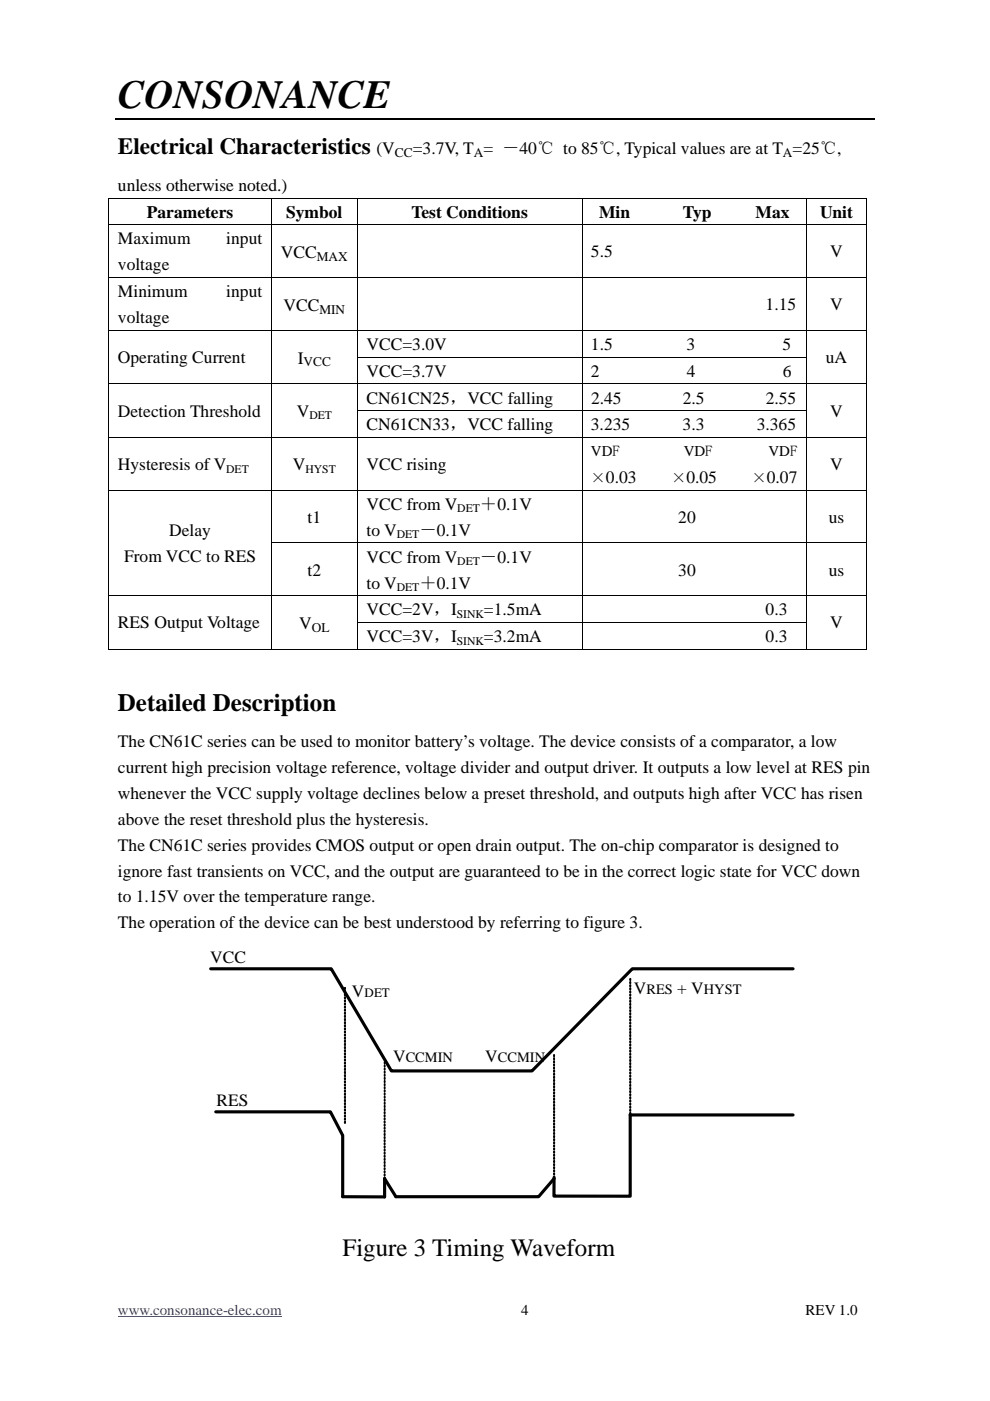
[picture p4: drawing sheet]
<svg xmlns="http://www.w3.org/2000/svg" width="210mm" height="297mm" viewBox="0 0 210 297" stroke-linecap="round" stroke-linejoin="round" font-family="sans-serif">
<defs><g id="words">
<text font-size="8.5" x="25" y="22.9">CONSONANCE</text>
<g font-size="5.3">
<text x="25" y="150.7">Detailed Description</text>
<text x="72.6" y="266.2">Figure 3 Timing Waveform</text>
</g>
<text font-size="4.9" x="25" y="32.7">Electrical Characteristics</text>
<g font-size="3.7">
<text x="79.9" y="32.7">(V</text>
<text x="87.5" y="32.7">=3.7V, T = －40℃ to 85℃, Typical values are at T =25℃,</text>
<text x="25" y="40.5">unless otherwise noted.)</text>
<text x="31.2" y="46.2">Parameters</text>
<text x="60.7" y="46.2">Symbol</text>
<text x="87.3" y="46.2">Test Conditions</text>
<text x="127.1" y="46.2">Min</text>
<text x="144.8" y="46.2">Typ</text>
<text x="160.3" y="46.2">Max</text>
<text x="173.9" y="46.2">Unit</text>
<text x="25" y="51.8">Maximum</text>
<text x="48" y="51.8">input</text>
<text x="25" y="57.3">voltage</text>
<text x="59.6" y="54.8">VCC</text>
<text x="125.3" y="54.6">5.5</text>
<text x="176.1" y="54.6">V</text>
<text x="25" y="63">Minimum</text>
<text x="48" y="63">input</text>
<text x="60.1" y="66">VCC</text>
<text x="162.4" y="65.8">1.15</text>
<text x="176.1" y="65.8">V</text>
<text x="25" y="68.5">voltage</text>
<text x="25" y="76.9">Operating Current</text>
<text x="63.2" y="77.1">I</text>
<text x="77.7" y="74.2">VCC=3.0V</text>
<text x="125.4" y="74.2">1.5</text>
<text x="145.6" y="74.2">3</text>
<text x="165.9" y="74.2">5</text>
<text x="175.2" y="76.9">uA</text>
<text x="77.7" y="79.9">VCC=3.7V</text>
<text x="125.3" y="79.9">2</text>
<text x="145.7" y="79.9">4</text>
<text x="166.1" y="79.9">6</text>
<text x="25" y="88.3">Detection Threshold</text>
<text x="63" y="88.3">V</text>
<text x="77.7" y="85.6">CN61CN25，VCC falling</text>
<text x="125.4" y="85.6">2.45</text>
<text x="144.8" y="85.6">2.5</text>
<text x="162.4" y="85.6">2.55</text>
<text x="176.1" y="88.3">V</text>
<text x="77.7" y="91.2">CN61CN33，VCC falling</text>
<text x="125.3" y="91.2">3.235</text>
<text x="144.8" y="91.2">3.3</text>
<text x="160.5" y="91.2">3.365</text>
<text x="25" y="99.7">Hysteresis of V</text>
<text x="62.1" y="99.7">V</text>
<text x="77.7" y="99.7">VCC rising</text>
<text x="176.1" y="99.7">V</text>
<text x="128.5" y="102.3">0.03</text>
<text x="145.6" y="102.3">0.05</text>
<text x="162.7" y="102.3">0.07</text>
<text x="35.9" y="113.6">Delay</text>
<text x="65.2" y="110.8">t1</text>
<text x="77.7" y="108.1">VCC from V</text>
<text x="77.7" y="113.6">to V</text>
<text x="88.9" y="113.6">－0.1V</text>
<text x="101.8" y="108.1">＋0.1V</text>
<text x="143.9" y="110.8">20</text>
<text x="175.8" y="110.8">us</text>
<text x="26.3" y="119.1">From VCC to RES</text>
<text x="77.7" y="119.3">VCC from V</text>
<text x="101.8" y="119.3">－0.1V</text>
<text x="65.2" y="122">t2</text>
<text x="77.7" y="124.8">to V</text>
<text x="88.9" y="124.8">＋0.1V</text>
<text x="143.9" y="122">30</text>
<text x="175.8" y="122">us</text>
<text x="77.7" y="130.5">VCC=2V，I</text>
<text x="102.6" y="130.5">=1.5mA</text>
<text x="162.4" y="130.5">0.3</text>
<text x="25" y="133.2">RES Output Voltage</text>
<text x="63.5" y="133.4">V</text>
<text x="77.7" y="136.1">VCC=3V，I</text>
<text x="102.6" y="136.1">=3.2mA</text>
<text x="162.4" y="136.1">0.3</text>
<text x="176.1" y="133.2">V</text>
<text x="25" y="158.3">The CN61C series can be used to monitor battery’s voltage. The device consists of a comparator, a low</text>
<text x="25" y="163.8">current high precision voltage reference, voltage divider and output driver. It outputs a low level at RES pin</text>
<text x="25" y="169.3">whenever the VCC supply voltage declines below a preset threshold, and outputs high after VCC has risen</text>
<text x="25" y="174.8">above the reset threshold plus the hysteresis.</text>
<text x="25" y="180.3">The CN61C series provides CMOS output or open drain output. The on-chip comparator is designed to</text>
<text x="25" y="185.8">ignore fast transients on VCC, and the output are guaranteed to be in the correct logic state for VCC down</text>
<text x="25" y="191.3">to 1.15V over the temperature range.</text>
<text x="25" y="196.8">The operation of the device can be best understood by referring to figure 3.</text>
<text x="44.6" y="204.2">VCC</text>
<text x="74.7" y="211.5">V</text>
<text x="134.5" y="210.8">V</text>
<text x="143.6" y="210.8">+ V</text>
<text x="83.4" y="225.1">V</text>
<text x="102.9" y="225.1">V</text>
<text x="46" y="234.5">RES</text>
</g>
<g font-size="3.2">
<text x="125.3" y="96.7">VDF</text>
<text x="145" y="96.7">VDF</text>
<text x="163" y="96.7">VDF</text>
<text x="125.3" y="102.3">×</text>
<text x="142.4" y="102.3">×</text>
<text x="159.5" y="102.3">×</text>
<text x="110.5" y="278.7">4</text>
<text x="170.9" y="278.7">REV 1.0</text>
</g>
<text font-size="3.2" fill="#00f" x="25" y="278.7">www.consonance-elec.com</text>
<g font-size="3">
<text x="137.1" y="210.8">RES</text>
<text x="149.3" y="210.8">HYST</text>
<text x="86" y="225.1">CCMIN</text>
<text x="105.6" y="225.1">CCMIN</text>
</g>
<g font-size="2.8">
<text x="83.8" y="33.3">CC</text>
<text x="100.5" y="33.3">A</text>
<text x="166.1" y="33.3">A</text>
<text x="67.2" y="55.3">MAX</text>
<text x="67.8" y="66.5">MIN</text>
<text x="64.4" y="77.7">VCC</text>
<text x="66.1" y="133.9">OL</text>
<text x="77.3" y="211.5">DET</text>
</g>
<g font-size="2.5">
<text x="65.6" y="88.8">DET</text>
<text x="48" y="100.2">DET</text>
<text x="64.8" y="100.2">HYST</text>
<text x="97" y="108.6">DET</text>
<text x="84.2" y="114.1">DET</text>
<text x="97" y="119.8">DET</text>
<text x="84.2" y="125.3">DET</text>
<text x="96.9" y="131">SINK</text>
<text x="96.9" y="136.7">SINK</text>
</g>
</g></defs>
<path d="M24.5 25.2h161" fill="none" stroke="#000" stroke-width=".25"/>
<path d="M25 279.2h34.7" fill="none" stroke="#00f" stroke-width=".21"/>
<g fill="#000">
<path d="M23 41.9h.2v.2h-.2zM183.7 41.9h.2v.2h-.2zM23 75.6h.2v.2h-.2zM57.4 75.6h.2v.2h-.2zM183.7 75.6h.2v.2h-.2zM23 87h.2v.2h-.2zM57.4 87h.2v.2h-.2zM183.7 87h.2v.2h-.2zM23 115h.2v.2h-.2zM23 131.9h.2v.2h-.2zM57.4 131.9h.2v.2h-.2zM183.7 131.9h.2v.2h-.2z"/>
<path d="M183.7 137.6h.2v.2h-.2z"/>
</g>
<g fill="none" stroke="#000" stroke-width=".21">
<path d="M23 42h160.9M23 47.7h160.9M23 58.9h160.9M23.1 42.1v5.5M23.1 47.8v11M23.1 58.9v11.1M57.5 42.1v5.5M57.5 47.8v11M57.5 58.9v11.1M75.8 42.1v5.5M75.8 47.8v11M75.8 58.9v11.1"/>
<path d="M123.4 42.1v5.5M123.4 47.8v11M123.4 58.9v11.1M171.1 42.1v5.5M171.1 47.8v11M171.1 58.9v11.1M183.8 42.1v5.5M183.8 47.8v11M183.8 58.9v11.1M23 70h160.9M23.1 70.1v5.5M23.1 75.8v5.5"/>
<path d="M57.5 70.1v5.5M57.5 75.8v5.5M75.7 75.7h95.5M75.8 70.1v5.5M75.8 75.8v5.5M123.4 70.1v5.5M123.4 75.8v5.5M171.1 70.1v5.5M171.1 75.8v5.5M183.8 70.1v5.5M183.8 75.8v5.5M23 81.4h160.9"/>
<path d="M23 92.8h160.9M23.1 81.5v5.5M23.1 87.2v5.5M23.1 92.8v11.1M57.5 81.5v5.5M57.5 87.2v5.5M57.5 92.8v11.1M75.7 87.1h95.5M75.8 81.5v5.5M75.8 87.2v5.5M75.8 92.8v11.1M123.4 81.5v5.5"/>
<path d="M123.4 87.2v5.5M123.4 92.8v11.1M171.1 81.5v5.5M171.1 87.2v5.5M171.1 92.8v11.1M183.8 81.5v5.5M183.8 87.2v5.5M183.8 92.8v11.1M23 103.9h160.9M23.1 104v11M23.1 115.2v11M57.4 115.1h126.5"/>
<path d="M57.5 104v11M57.5 115.2v11M75.8 104v11M75.8 115.2v11M123.4 104v11M123.4 115.2v11M171.1 104v11M171.1 115.2v11M183.8 104v11M183.8 115.2v11M23 126.3h160.9M23 137.7h34.4"/>
<path d="M23.1 126.4v5.5M23.1 132.1v5.7M57.5 126.4v5.5M57.5 132.1v5.7M57.6 137.7h18.1M75.7 132h95.5M75.8 126.4v5.5M75.8 132.1v5.7M75.9 137.7h47.5M123.4 126.4v5.5M123.4 132.1v5.7M123.5 137.7h47.5"/>
<path d="M171.1 126.4v5.5M171.1 132.1v5.7M171.2 137.7h12.5M183.8 126.4v5.5M183.8 132.1v5.7"/>
</g>
<path d="M44.7 205.4h25.6l12.7 21.7h29.8l21.3-21.7h34.1M45.8 235.7h24.3l2.6 5v13l8.9 .1v-3.9l2.4 3.8h30.2l3.3-3.8M133.7 236.3v17.3h-16.2v-4M133.7 236.4h34.5" fill="none" stroke="#000" stroke-width=".66"/>
<g fill="#000" stroke="#000" stroke-width=".21">
<path d="M73 209.4h.3v.3h-.3zM73.1 210h.2v.4l-.3-.1zM73.1 210.7h.2v.4l-.3-.1zM73.1 211.3h.2v.4l-.3-.1zM73.1 212l.2 .1-.1 .3-.2-.1zM73 212.7h.3v.3h-.3zM73.1 213.3h.2v.4l-.3-.1zM73.1 214h.2v.4l-.3-.1zM73.1 214.7h.2v.3l-.3-.1zM73.1 215.3l.2 .1-.1 .3-.2-.1zM73 216h.3v.3h-.3zM73.1 216.6h.2v.4l-.3-.1zM73.1 217.3h.2v.4l-.3-.1zM73.1 218h.2v.3l-.3-.1zM73.1 218.6l.2 .1-.1 .3-.2-.1zM73.1 219.3l.2 .1-.1 .3-.2-.1zM73.1 219.9h.2v.4l-.3-.1zM73.1 220.6h.2v.4l-.3-.1zM73.1 221.3h.2v.3h-.3zM73.1 221.9l.2 .1-.1 .3-.2-.1zM73.1 222.6l.2 .1-.1 .3-.2-.1zM73.1 223.2h.2v.4l-.3-.1zM73.1 223.9h.2v.4l-.3-.1zM73.1 224.6h.2v.3h-.3zM73.1 225.2l.2 .1-.1 .3-.2-.1zM73.1 225.9l.2 .1-.1 .3-.2-.1zM73.1 226.5h.2v.4l-.3-.1zM73.1 227.2h.2v.4l-.3-.1zM73.1 227.9h.2v.3h-.3zM73.1 228.5l.2 .1-.1 .3-.2-.1zM73.1 229.2l.2 .1-.1 .3-.2-.1zM73.1 229.8h.2v.4l-.3-.1zM73.1 230.5h.2v.4l-.3-.1zM73.1 231.2h.2v.3h-.3zM73.1 231.8l.2 .1-.1 .3-.2-.1zM73.1 232.5l.2 .1-.1 .3-.2-.1zM73.1 233.2h.2v.3l-.3-.1zM73.1 233.8h.2v.4l-.3-.1zM73.1 234.5h.2v.3h-.3zM73.1 235.1l.2 .1-.1 .3-.2-.1zM73.1 235.8l.2 .1-.1 .3-.2-.1zM73.1 236.5h.2v.3l-.3-.1zM73.1 237.1h.2v.4l-.3-.1zM73.1 237.8h.2l-.1 .4-.2-.1z"/>
<path d="M133.6 207.5h.2v.4l-.2-.1zM133.6 208.1h.2v.4h-.2zM133.6 208.8h.2v.4l-.2-.1zM133.6 209.5h.2l-.1 .4zM133.7 210.1l.1 .1-.1 .3zM133.6 210.8h.2v.4l-.2-.1zM133.6 211.4h.2v.4h-.2zM133.6 212.1h.2v.4l-.2-.1zM133.6 212.8h.2l-.1 .4zM133.7 213.4l.1 .1-.1 .3zM133.6 214.1h.2v.4l-.2-.1zM133.6 214.7h.2v.4h-.2zM133.6 215.4h.2v.4l-.2-.1zM133.6 216.1h.2l-.1 .4zM133.7 216.7l.1 .1-.1 .3zM133.6 217.4h.2v.4l-.2-.1zM133.6 218h.2v.4h-.2zM133.6 218.7h.2v.4l-.2-.1zM133.6 219.4h.2l-.1 .4zM133.7 220l.1 .1-.1 .3zM133.6 220.7h.2v.4l-.2-.1zM133.6 221.3h.2v.4h-.2zM133.6 222h.2v.4l-.2-.1zM133.6 222.7h.2l-.1 .4zM133.6 223.4h.2v.3l-.2-.1zM133.6 224h.2v.4l-.2-.1zM133.6 224.6h.2v.4h-.2zM133.6 225.3h.2v.4l-.2-.1zM133.6 226h.2l-.1 .4zM133.7 226.6l.1 .1-.1 .3zM133.6 227.3h.2v.4l-.2-.1zM133.6 227.9h.2v.4h-.2zM133.6 228.6h.2v.4l-.2-.1zM133.6 229.3h.2l-.1 .4zM133.7 229.9l.1 .1-.1 .3zM133.6 230.6h.2v.4l-.2-.1zM133.6 231.2h.2v.4h-.2zM133.6 231.9h.2v.4l-.2-.1zM133.6 232.6h.2l-.1 .4zM133.6 233.3h.2v.3h-.2zM133.6 233.9h.2v.4l-.2-.1zM133.6 234.5h.2v.4h-.2zM133.6 235.2h.2v.4l-.2-.1zM133.6 235.9h.2l-.1 .4z"/>
<path d="M117.4 223.6l.2 .1-.1 .3zM117.4 224.3h.2l-.1 .4zM117.4 224.9h.2v.4h-.2zM117.4 225.6h.2v.4h-.2zM117.4 226.3h.2v.4h-.2zM117.4 226.9l.2 .1-.1 .3zM117.4 227.6h.2l-.1 .4zM117.4 228.2l.2 .1v.3h-.2zM117.4 228.9l.2 .1v.3h-.2zM117.4 229.6h.2v.4h-.2zM117.4 230.2l.2 .1-.1 .3zM117.4 230.9h.2l-.1 .4zM117.4 231.5l.2 .1v.3h-.2zM117.4 232.2l.2 .1v.3h-.2zM117.4 232.9h.2v.4h-.2zM117.4 233.5l.2 .1-.1 .3zM117.4 234.2l.2 .1-.1 .3zM117.4 234.8l.2 .1v.3h-.2zM117.4 235.5l.2 .1v.3h-.2zM117.4 236.2h.2v.4h-.2zM117.4 236.8l.2 .1-.1 .3zM117.4 237.5l.2 .1-.1 .3zM117.4 238.1l.2 .1v.3h-.2zM117.4 238.8l.2 .1v.3l-.2-.1zM117.5 239.5l.1 .1v.3l-.2-.1zM117.5 240.1l.1 .1-.1 .3zM117.5 240.8l.1 .1-.1 .3zM117.5 241.4l.1 .1v.3h-.2zM117.5 242.1l.1 .1v.3l-.2-.1zM117.5 242.8l.1 .1v.3l-.2-.1zM117.5 243.4l.1 .1-.1 .3zM117.5 244.1l.1 .1-.1 .3zM117.5 244.8h.1v.3h-.2zM117.5 245.4l.1 .1v.3l-.2-.1zM117.5 246.1l.1 .1v.3l-.2-.1zM117.5 246.7l.1 .1-.1 .3zM117.5 247.4l.1 .1-.1 .3zM117.5 248.1h.1v.3h-.2zM117.5 248.7l.1 .1v.3l-.2-.1zM117.5 249.4l.1 .1-.1 .3z"/>
<path d="M81.5 249.6l.2 .1-.1 .3zM81.6 248.9v.4zM81.5 248.3h.2l-.1 .4zM81.5 247.6l.2 .1-.1 .3zM81.5 246.9l.2 .1-.1 .4zM81.5 246.3h.2v.4l-.2-.1zM81.5 245.6l.2 .1-.1 .3zM81.5 245h.2l-.1 .4zM81.5 244.3h.2v.4l-.2-.1zM81.5 243.6h.2v.4l-.2-.1zM81.5 243h.2v.4l-.2-.1zM81.6 242.3v.4zM81.5 241.7h.2l-.1 .4zM81.5 241h.2v.4l-.2-.1zM81.5 240.3h.2v.4l-.2-.1zM81.5 239.7h.2v.4l-.2-.1zM81.5 239l.2 .1-.1 .3zM81.5 238.4h.2l-.1 .4zM81.5 237.7h.2v.4l-.2-.1zM81.5 237h.2v.4l-.2-.1zM81.5 236.4h.2v.3h-.2zM81.6 235.7v.4zM81.5 235.1h.2l-.1 .4zM81.5 234.4h.2v.4h-.2zM81.5 233.7h.2v.4h-.2zM81.5 233.1h.2v.3h-.2zM81.6 232.4v.4zM81.5 231.8h.2l-.1 .4zM81.5 231.1h.2v.4h-.2zM81.5 230.4h.2v.4h-.2zM81.5 229.8h.2v.3h-.2zM81.6 229.1v.4zM81.5 228.5h.2l-.1 .4zM81.5 227.8h.2v.4h-.2zM81.5 227.1h.2v.4h-.2zM81.5 226.5h.2v.3h-.2zM81.6 225.8v.4zM81.5 225.1l.2 .1-.1 .4z"/>
</g>
<use href="#words"/>
</svg>
